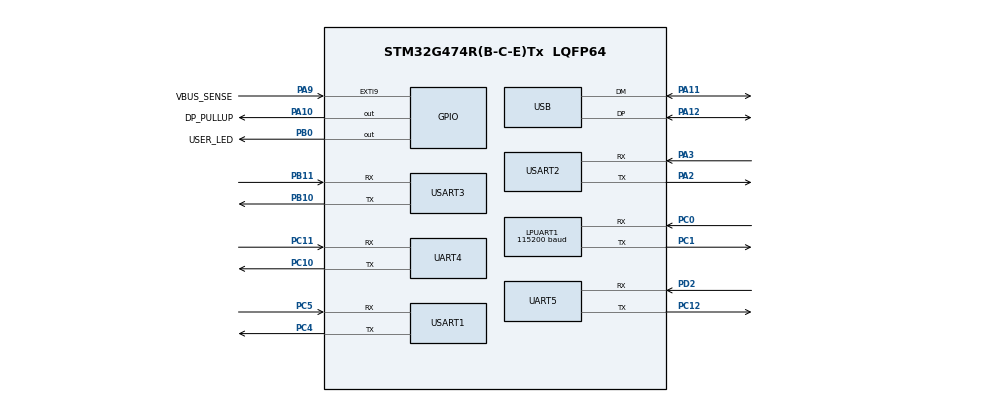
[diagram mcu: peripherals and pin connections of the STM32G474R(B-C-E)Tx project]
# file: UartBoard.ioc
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Dma.LPUART1_RX.0.Direction=DMA_PERIPH_TO_MEMORY
Dma.LPUART1_RX.0.EventEnable=DISABLE
Dma.LPUART1_RX.0.Instance=DMA1_Channel1
Dma.LPUART1_RX.0.MemDataAlignment=DMA_MDATAALIGN_BYTE
Dma.LPUART1_RX.0.MemInc=DMA_MINC_ENABLE
Dma.LPUART1_RX.0.Mode=DMA_NORMAL
Dma.LPUART1_RX.0.PeriphDataAlignment=DMA_PDATAALIGN_BYTE
Dma.LPUART1_RX.0.PeriphInc=DMA_PINC_DISABLE
Dma.LPUART1_RX.0.Polarity=HAL_DMAMUX_REQ_GEN_RISING
Dma.LPUART1_RX.0.Priority=DMA_PRIORITY_LOW
Dma.LPUART1_RX.0.RequestNumber=1
Dma.LPUART1_RX.0.SignalID=NONE
Dma.LPUART1_RX.0.SyncEnable=DISABLE
Dma.LPUART1_RX.0.SyncPolarity=HAL_DMAMUX_SYNC_NO_EVENT
Dma.LPUART1_RX.0.SyncRequestNumber=1
Dma.LPUART1_RX.0.SyncSignalID=NONE
Dma.LPUART1_TX.1.Direction=DMA_MEMORY_TO_PERIPH
Dma.LPUART1_TX.1.EventEnable=DISABLE
Dma.LPUART1_TX.1.Instance=DMA1_Channel2
Dma.LPUART1_TX.1.MemDataAlignment=DMA_MDATAALIGN_BYTE
Dma.LPUART1_TX.1.MemInc=DMA_MINC_ENABLE
Dma.LPUART1_TX.1.Mode=DMA_NORMAL
Dma.LPUART1_TX.1.PeriphDataAlignment=DMA_PDATAALIGN_BYTE
Dma.LPUART1_TX.1.PeriphInc=DMA_PINC_DISABLE
Dma.LPUART1_TX.1.Polarity=HAL_DMAMUX_REQ_GEN_RISING
Dma.LPUART1_TX.1.Priority=DMA_PRIORITY_LOW
Dma.LPUART1_TX.1.RequestNumber=1
Dma.LPUART1_TX.1.SignalID=NONE
Dma.LPUART1_TX.1.SyncEnable=DISABLE
Dma.LPUART1_TX.1.SyncPolarity=HAL_DMAMUX_SYNC_NO_EVENT
Dma.LPUART1_TX.1.SyncRequestNumber=1
Dma.LPUART1_TX.1.SyncSignalID=NONE
Dma.Request0=LPUART1_RX
Dma.Request1=LPUART1_TX
Dma.Request10=UART5_RX
Dma.Request11=UART5_TX
Dma.Request2=USART1_RX
Dma.Request3=USART1_TX
Dma.Request4=USART2_RX
Dma.Request5=USART2_TX
Dma.Request6=USART3_RX
Dma.Request7=USART3_TX
Dma.Request8=UART4_RX
Dma.Request9=UART4_TX
Dma.UART4_RX.8.Direction=DMA_PERIPH_TO_MEMORY
Dma.UART4_RX.8.EventEnable=DISABLE
Dma.UART4_RX.8.Instance=DMA2_Channel1
Dma.UART4_RX.8.MemDataAlignment=DMA_MDATAALIGN_BYTE
Dma.UART4_RX.8.MemInc=DMA_MINC_ENABLE
Dma.UART4_RX.8.Mode=DMA_NORMAL
Dma.UART4_RX.8.PeriphDataAlignment=DMA_PDATAALIGN_BYTE
Dma.UART4_RX.8.PeriphInc=DMA_PINC_DISABLE
Dma.UART4_RX.8.Polarity=HAL_DMAMUX_REQ_GEN_RISING
Dma.UART4_RX.8.Priority=DMA_PRIORITY_LOW
Dma.UART4_RX.8.RequestNumber=1
Dma.UART4_RX.8.SignalID=NONE
Dma.UART4_RX.8.SyncEnable=DISABLE
Dma.UART4_RX.8.SyncPolarity=HAL_DMAMUX_SYNC_NO_EVENT
Dma.UART4_RX.8.SyncRequestNumber=1
Dma.UART4_RX.8.SyncSignalID=NONE
Dma.UART4_TX.9.Direction=DMA_MEMORY_TO_PERIPH
Dma.UART4_TX.9.EventEnable=DISABLE
Dma.UART4_TX.9.Instance=DMA2_Channel2
Dma.UART4_TX.9.MemDataAlignment=DMA_MDATAALIGN_BYTE
Dma.UART4_TX.9.MemInc=DMA_MINC_ENABLE
Dma.UART4_TX.9.Mode=DMA_NORMAL
Dma.UART4_TX.9.PeriphDataAlignment=DMA_PDATAALIGN_BYTE
Dma.UART4_TX.9.PeriphInc=DMA_PINC_DISABLE
Dma.UART4_TX.9.Polarity=HAL_DMAMUX_REQ_GEN_RISING
Dma.UART4_TX.9.Priority=DMA_PRIORITY_LOW
Dma.UART4_TX.9.RequestNumber=1
Dma.UART4_TX.9.SignalID=NONE
Dma.UART4_TX.9.SyncEnable=DISABLE
Dma.UART4_TX.9.SyncPolarity=HAL_DMAMUX_SYNC_NO_EVENT
Dma.UART4_TX.9.SyncRequestNumber=1
Dma.UART4_TX.9.SyncSignalID=NONE
Dma.UART5_RX.10.Direction=DMA_PERIPH_TO_MEMORY
Dma.UART5_RX.10.EventEnable=DISABLE
Dma.UART5_RX.10.Instance=DMA2_Channel3
Dma.UART5_RX.10.MemDataAlignment=DMA_MDATAALIGN_BYTE
Dma.UART5_RX.10.MemInc=DMA_MINC_ENABLE
Dma.UART5_RX.10.Mode=DMA_NORMAL
Dma.UART5_RX.10.PeriphDataAlignment=DMA_PDATAALIGN_BYTE
Dma.UART5_RX.10.PeriphInc=DMA_PINC_DISABLE
Dma.UART5_RX.10.Polarity=HAL_DMAMUX_REQ_GEN_RISING
Dma.UART5_RX.10.Priority=DMA_PRIORITY_LOW
Dma.UART5_RX.10.RequestNumber=1
Dma.UART5_RX.10.SignalID=NONE
Dma.UART5_RX.10.SyncEnable=DISABLE
Dma.UART5_RX.10.SyncPolarity=HAL_DMAMUX_SYNC_NO_EVENT
Dma.UART5_RX.10.SyncRequestNumber=1
Dma.UART5_RX.10.SyncSignalID=NONE
Dma.UART5_TX.11.Direction=DMA_MEMORY_TO_PERIPH
Dma.UART5_TX.11.EventEnable=DISABLE
Dma.UART5_TX.11.Instance=DMA2_Channel4
Dma.UART5_TX.11.MemDataAlignment=DMA_MDATAALIGN_BYTE
Dma.UART5_TX.11.MemInc=DMA_MINC_ENABLE
Dma.UART5_TX.11.Mode=DMA_NORMAL
Dma.UART5_TX.11.PeriphDataAlignment=DMA_PDATAALIGN_BYTE
Dma.UART5_TX.11.PeriphInc=DMA_PINC_DISABLE
Dma.UART5_TX.11.Polarity=HAL_DMAMUX_REQ_GEN_RISING
Dma.UART5_TX.11.Priority=DMA_PRIORITY_LOW
Dma.UART5_TX.11.RequestNumber=1
Dma.UART5_TX.11.SignalID=NONE
Dma.UART5_TX.11.SyncEnable=DISABLE
Dma.UART5_TX.11.SyncPolarity=HAL_DMAMUX_SYNC_NO_EVENT
Dma.UART5_TX.11.SyncRequestNumber=1
Dma.UART5_TX.11.SyncSignalID=NONE
Dma.USART1_RX.2.Direction=DMA_PERIPH_TO_MEMORY
Dma.USART1_RX.2.EventEnable=DISABLE
Dma.USART1_RX.2.Instance=DMA1_Channel3
Dma.USART1_RX.2.MemDataAlignment=DMA_MDATAALIGN_BYTE
Dma.USART1_RX.2.MemInc=DMA_MINC_ENABLE
Dma.USART1_RX.2.Mode=DMA_NORMAL
Dma.USART1_RX.2.PeriphDataAlignment=DMA_PDATAALIGN_BYTE
Dma.USART1_RX.2.PeriphInc=DMA_PINC_DISABLE
Dma.USART1_RX.2.Polarity=HAL_DMAMUX_REQ_GEN_RISING
Dma.USART1_RX.2.Priority=DMA_PRIORITY_LOW
Dma.USART1_RX.2.RequestNumber=1
Dma.USART1_RX.2.SignalID=NONE
Dma.USART1_RX.2.SyncEnable=DISABLE
Dma.USART1_RX.2.SyncPolarity=HAL_DMAMUX_SYNC_NO_EVENT
Dma.USART1_RX.2.SyncRequestNumber=1
Dma.USART1_RX.2.SyncSignalID=NONE
Dma.USART1_TX.3.Direction=DMA_MEMORY_TO_PERIPH
Dma.USART1_TX.3.EventEnable=DISABLE
Dma.USART1_TX.3.Instance=DMA1_Channel4
Dma.USART1_TX.3.MemDataAlignment=DMA_MDATAALIGN_BYTE
Dma.USART1_TX.3.MemInc=DMA_MINC_ENABLE
Dma.USART1_TX.3.Mode=DMA_NORMAL
Dma.USART1_TX.3.PeriphDataAlignment=DMA_PDATAALIGN_BYTE
Dma.USART1_TX.3.PeriphInc=DMA_PINC_DISABLE
Dma.USART1_TX.3.Polarity=HAL_DMAMUX_REQ_GEN_RISING
Dma.USART1_TX.3.Priority=DMA_PRIORITY_LOW
Dma.USART1_TX.3.RequestNumber=1
Dma.USART1_TX.3.SignalID=NONE
Dma.USART1_TX.3.SyncEnable=DISABLE
Dma.USART1_TX.3.SyncPolarity=HAL_DMAMUX_SYNC_NO_EVENT
Dma.USART1_TX.3.SyncRequestNumber=1
Dma.USART1_TX.3.SyncSignalID=NONE
Dma.USART2_RX.4.Direction=DMA_PERIPH_TO_MEMORY
Dma.USART2_RX.4.EventEnable=DISABLE
Dma.USART2_RX.4.Instance=DMA1_Channel5
Dma.USART2_RX.4.MemDataAlignment=DMA_MDATAALIGN_BYTE
Dma.USART2_RX.4.MemInc=DMA_MINC_ENABLE
Dma.USART2_RX.4.Mode=DMA_NORMAL
Dma.USART2_RX.4.PeriphDataAlignment=DMA_PDATAALIGN_BYTE
Dma.USART2_RX.4.PeriphInc=DMA_PINC_DISABLE
Dma.USART2_RX.4.Polarity=HAL_DMAMUX_REQ_GEN_RISING
Dma.USART2_RX.4.Priority=DMA_PRIORITY_LOW
Dma.USART2_RX.4.RequestNumber=1
Dma.USART2_RX.4.SignalID=NONE
Dma.USART2_RX.4.SyncEnable=DISABLE
Dma.USART2_RX.4.SyncPolarity=HAL_DMAMUX_SYNC_NO_EVENT
Dma.USART2_RX.4.SyncRequestNumber=1
Dma.USART2_RX.4.SyncSignalID=NONE
Dma.USART2_TX.5.Direction=DMA_MEMORY_TO_PERIPH
Dma.USART2_TX.5.EventEnable=DISABLE
Dma.USART2_TX.5.Instance=DMA1_Channel6
Dma.USART2_TX.5.MemDataAlignment=DMA_MDATAALIGN_BYTE
Dma.USART2_TX.5.MemInc=DMA_MINC_ENABLE
Dma.USART2_TX.5.Mode=DMA_NORMAL
Dma.USART2_TX.5.PeriphDataAlignment=DMA_PDATAALIGN_BYTE
Dma.USART2_TX.5.PeriphInc=DMA_PINC_DISABLE
Dma.USART2_TX.5.Polarity=HAL_DMAMUX_REQ_GEN_RISING
Dma.USART2_TX.5.Priority=DMA_PRIORITY_LOW
Dma.USART2_TX.5.RequestNumber=1
Dma.USART2_TX.5.SignalID=NONE
Dma.USART2_TX.5.SyncEnable=DISABLE
Dma.USART2_TX.5.SyncPolarity=HAL_DMAMUX_SYNC_NO_EVENT
Dma.USART2_TX.5.SyncRequestNumber=1
Dma.USART2_TX.5.SyncSignalID=NONE
Dma.USART3_RX.6.Direction=DMA_PERIPH_TO_MEMORY
Dma.USART3_RX.6.EventEnable=DISABLE
Dma.USART3_RX.6.Instance=DMA1_Channel7
Dma.USART3_RX.6.MemDataAlignment=DMA_MDATAALIGN_BYTE
Dma.USART3_RX.6.MemInc=DMA_MINC_ENABLE
Dma.USART3_RX.6.Mode=DMA_NORMAL
Dma.USART3_RX.6.PeriphDataAlignment=DMA_PDATAALIGN_BYTE
Dma.USART3_RX.6.PeriphInc=DMA_PINC_DISABLE
Dma.USART3_RX.6.Polarity=HAL_DMAMUX_REQ_GEN_RISING
Dma.USART3_RX.6.Priority=DMA_PRIORITY_LOW
Dma.USART3_RX.6.RequestNumber=1
Dma.USART3_RX.6.SignalID=NONE
Dma.USART3_RX.6.SyncEnable=DISABLE
Dma.USART3_RX.6.SyncPolarity=HAL_DMAMUX_SYNC_NO_EVENT
Dma.USART3_RX.6.SyncRequestNumber=1
Dma.USART3_RX.6.SyncSignalID=NONE
Dma.USART3_TX.7.Direction=DMA_MEMORY_TO_PERIPH
Dma.USART3_TX.7.EventEnable=DISABLE
Dma.USART3_TX.7.Instance=DMA1_Channel8
Dma.USART3_TX.7.MemDataAlignment=DMA_MDATAALIGN_BYTE
Dma.USART3_TX.7.MemInc=DMA_MINC_ENABLE
Dma.USART3_TX.7.Mode=DMA_NORMAL
Dma.USART3_TX.7.PeriphDataAlignment=DMA_PDATAALIGN_BYTE
Dma.USART3_TX.7.PeriphInc=DMA_PINC_DISABLE
Dma.USART3_TX.7.Polarity=HAL_DMAMUX_REQ_GEN_RISING
Dma.USART3_TX.7.Priority=DMA_PRIORITY_LOW
Dma.USART3_TX.7.RequestNumber=1
Dma.USART3_TX.7.SignalID=NONE
Dma.USART3_TX.7.SyncEnable=DISABLE
Dma.USART3_TX.7.SyncPolarity=HAL_DMAMUX_SYNC_NO_EVENT
Dma.USART3_TX.7.SyncRequestNumber=1
Dma.USART3_TX.7.SyncSignalID=NONE
LPUART1.BaudRate=115200
Mcu.Family=STM32G4
Mcu.Name=STM32G474R(B-C-E)Tx
Mcu.Package=LQFP64
NVIC.DMA1_Channel1_IRQn=true\:0\:0\:false\:false\:true\:false\:true\:true
NVIC.DMA1_Channel2_IRQn=true\:0\:0\:false\:false\:true\:false\:true\:true
NVIC.DMA1_Channel3_IRQn=true\:0\:0\:false\:false\:true\:false\:true\:true
NVIC.DMA1_Channel4_IRQn=true\:0\:0\:false\:false\:true\:false\:true\:true
NVIC.DMA1_Channel5_IRQn=true\:0\:0\:false\:false\:true\:false\:true\:true
NVIC.DMA1_Channel6_IRQn=true\:0\:0\:false\:false\:true\:false\:true\:true
NVIC.DMA1_Channel7_IRQn=true\:0\:0\:false\:false\:true\:false\:true\:true
NVIC.DMA1_Channel8_IRQn=true\:0\:0\:false\:false\:true\:false\:true\:true
NVIC.DMA2_Channel1_IRQn=true\:0\:0\:false\:false\:true\:false\:true\:true
NVIC.DMA2_Channel2_IRQn=true\:0\:0\:false\:false\:true\:false\:true\:true
NVIC.DMA2_Channel3_IRQn=true\:0\:0\:false\:false\:true\:false\:true\:true
NVIC.DMA2_Channel4_IRQn=true\:0\:0\:false\:false\:true\:false\:true\:true
NVIC.LPUART1_IRQn=true\:0\:0\:false\:false\:true\:true\:true\:true
NVIC.PriorityGroup=NVIC_PRIORITYGROUP_4
NVIC.UART4_IRQn=true\:0\:0\:false\:false\:true\:true\:true\:true
NVIC.UART5_IRQn=true\:0\:0\:false\:false\:true\:true\:true\:true
NVIC.USART1_IRQn=true\:0\:0\:false\:false\:true\:true\:true\:true
NVIC.USART3_IRQn=true\:0\:0\:false\:false\:true\:true\:true\:true
NVIC.USB_HP_IRQn=true\:0\:0\:false\:false\:true\:true\:true\:true
NVIC.USB_LP_IRQn=true\:0\:0\:false\:false\:true\:true\:true\:true
PA10.GPIO_Label=DP_PULLUP
PA10.Signal=GPIO_Output
PA11.Mode=Device
PA11.Signal=USB_DM
PA12.Mode=Device
PA12.Signal=USB_DP
PA13.Mode=Trace_Asynchronous_SW
PA13.Signal=SYS_JTMS-SWDIO
PA14.Mode=Trace_Asynchronous_SW
PA14.Signal=SYS_JTCK-SWCLK
PA2.Mode=Asynchronous
PA2.Signal=USART2_TX
PA3.Mode=Asynchronous
PA3.Signal=USART2_RX
PA9.GPIO_Label=VBUS_SENSE
PA9.Signal=GPXTI9
PB0.GPIO_Label=USER_LED
PB0.Signal=GPIO_Output
PB10.Mode=Asynchronous
PB10.Signal=USART3_TX
PB11.Mode=Asynchronous
PB11.Signal=USART3_RX
PB3.Mode=Trace_Asynchronous_SW
PB3.Signal=SYS_JTDO-SWO
PC0.Mode=Asynchronous
PC0.Signal=LPUART1_RX
PC1.Mode=Asynchronous
PC1.Signal=LPUART1_TX
PC10.Mode=Asynchronous
PC10.Signal=UART4_TX
PC11.Mode=Asynchronous
PC11.Signal=UART4_RX
PC12.Mode=Asynchronous
PC12.Signal=UART5_TX
PC4.Mode=Asynchronous
PC4.Signal=USART1_TX
PC5.Mode=Asynchronous
PC5.Signal=USART1_RX
PD2.Mode=Asynchronous
PD2.Signal=UART5_RX
PF0-OSC_IN.Mode=HSE-External-Oscillator
PF0-OSC_IN.Signal=RCC_OSC_IN
PF1-OSC_OUT.Mode=HSE-External-Oscillator
PF1-OSC_OUT.Signal=RCC_OSC_OUT
ProjectManager.HeapSize=0x200
ProjectManager.StackSize=0x400
ProjectManager.TargetToolchain=CMake
RCC.ADC12Freq_Value=96000000
RCC.ADC345Freq_Value=96000000
RCC.AHBFreq_Value=96000000
RCC.APB1Freq_Value=96000000
RCC.APB1TimFreq_Value=96000000
RCC.APB2Freq_Value=96000000
RCC.APB2TimFreq_Value=96000000
RCC.CortexFreq_Value=96000000
RCC.EXTERNAL_CLOCK_VALUE=12288000
RCC.HCLKFreq_Value=96000000
RCC.HSE_VALUE=16000000
RCC.HSI48_VALUE=48000000
RCC.HSI_VALUE=16000000
RCC.LSE_VALUE=32768
RCC.PLLN=12
RCC.PLLQ=RCC_PLLQ_DIV4
RCC.PLLSourceVirtual=RCC_PLLSOURCE_HSE
RCC.SYSCLKFreq_VALUE=96000000
RCC.SYSCLKSource=RCC_SYSCLKSOURCE_PLLCLK
RCC.USBFreq_Value=48000000
RCC.VCOOutputFreq_Value=192000000
USART1.VirtualMode-Asynchronous=VM_ASYNC
USART2.VirtualMode-Asynchronous=VM_ASYNC
USART3.VirtualMode-Asynchronous=VM_ASYNC
VP_SYS_VS_DBSignals.Mode=DisableDeadBatterySignals
board=custom

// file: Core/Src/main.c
/* USER CODE BEGIN Header */
/**
  ******************************************************************************
  * @file           : main.c
  * @brief          : Main program body
  ******************************************************************************
  * @attention
  *
  * Copyright (c) 2026 STMicroelectronics.
  * All rights reserved.
  *
  * This software is licensed under terms that can be found in the LICENSE file
  * in the root directory of this software component.
  * If no LICENSE file comes with this software, it is provided AS-IS.
  *
  ******************************************************************************
  */
/* USER CODE END Header */
#include "main.h"

/* USER CODE BEGIN Includes */
// #include "device/dcd.h"
#include "tusb.h"
#include "serialization.h"
#include "deserialization.h"
#include <string.h>
#include <stdio.h>
/* USER CODE END Includes */

UART_HandleTypeDef hlpuart1;
UART_HandleTypeDef huart4;
UART_HandleTypeDef huart5;
UART_HandleTypeDef huart1;
UART_HandleTypeDef huart2;
UART_HandleTypeDef huart3;

PCD_HandleTypeDef hpcd_USB_FS;

/* USER CODE BEGIN PV */
uint8_t lpuart1_out_buf[64];
uint8_t uart1_out_buf[64];
uint8_t uart2_out_buf[64];
uint8_t uart3_out_buf[64];
uint8_t uart4_out_buf[64];
uint8_t uart5_out_buf[64];
/* USER CODE END PV */

void SystemClock_Config(void);
static void MX_GPIO_Init(void);
static void MX_LPUART1_UART_Init(void);
static void MX_UART4_Init(void);
static void MX_UART5_Init(void);
static void MX_USART1_UART_Init(void);
static void MX_USART2_UART_Init(void);
static void MX_USART3_UART_Init(void);
static void MX_USB_PCD_Init(void);

/* USER CODE BEGIN 0 */
static void cdc_task(void);
/* USER CODE END 0 */

int main(void)
{

  /* MCU Configuration--------------------------------------------------------*/

  /* Reset of all peripherals, Initializes the Flash interface and the Systick. */
  HAL_Init();

  /* Configure the system clock */
  SystemClock_Config();

  /* Initialize all configured peripherals */
  MX_GPIO_Init();
  MX_LPUART1_UART_Init();
  MX_UART4_Init();
  MX_UART5_Init();
  MX_USART1_UART_Init();
  MX_USART2_UART_Init();
  MX_USART3_UART_Init();
  MX_USB_PCD_Init();
  /* USER CODE BEGIN 2 */
 // init device stack on configured roothub port
  tusb_rhport_init_t dev_init = {
    .role = TUSB_ROLE_DEVICE,
    .speed = TUSB_SPEED_AUTO
  };
  tusb_init(BOARD_TUD_RHPORT, &dev_init);
  /* USER CODE END 2 */

  /* Infinite loop */
  /* USER CODE BEGIN WHILE */
  while (1)
  {
    tud_task(); // tinyusb device task
    cdc_task();
    /* USER CODE END WHILE */

  }
}

void SystemClock_Config(void)
{
  RCC_OscInitTypeDef RCC_OscInitStruct = {0};
  RCC_ClkInitTypeDef RCC_ClkInitStruct = {0};

  /** Configure the main internal regulator output voltage
  */
  HAL_PWREx_ControlVoltageScaling(PWR_REGULATOR_VOLTAGE_SCALE1);

  /** Initializes the RCC Oscillators according to the specified parameters
  * in the RCC_OscInitTypeDef structure.
  */
  RCC_OscInitStruct.OscillatorType = RCC_OSCILLATORTYPE_HSE;
  RCC_OscInitStruct.HSEState = RCC_HSE_ON;
  RCC_OscInitStruct.PLL.PLLState = RCC_PLL_ON;
  RCC_OscInitStruct.PLL.PLLSource = RCC_PLLSOURCE_HSE;
  RCC_OscInitStruct.PLL.PLLM = RCC_PLLM_DIV2;
  RCC_OscInitStruct.PLL.PLLN = 8;
  RCC_OscInitStruct.PLL.PLLP = RCC_PLLP_DIV2;
  RCC_OscInitStruct.PLL.PLLQ = RCC_PLLQ_DIV2;
  RCC_OscInitStruct.PLL.PLLR = RCC_PLLR_DIV2;
  if (HAL_RCC_OscConfig(&RCC_OscInitStruct) != HAL_OK)
  {
    Error_Handler();
  }

  /** Initializes the CPU, AHB and APB buses clocks
  */
  RCC_ClkInitStruct.ClockType = RCC_CLOCKTYPE_HCLK|RCC_CLOCKTYPE_SYSCLK
                              |RCC_CLOCKTYPE_PCLK1|RCC_CLOCKTYPE_PCLK2;
  RCC_ClkInitStruct.SYSCLKSource = RCC_SYSCLKSOURCE_PLLCLK;
  RCC_ClkInitStruct.AHBCLKDivider = RCC_SYSCLK_DIV2;
  RCC_ClkInitStruct.APB1CLKDivider = RCC_HCLK_DIV1;
  RCC_ClkInitStruct.APB2CLKDivider = RCC_HCLK_DIV1;

  if (HAL_RCC_ClockConfig(&RCC_ClkInitStruct, FLASH_LATENCY_0) != HAL_OK)
  {
    Error_Handler();
  }
}

static void MX_LPUART1_UART_Init(void)
{

  hlpuart1.Instance = LPUART1;
  hlpuart1.Init.BaudRate = 209700;
  hlpuart1.Init.WordLength = UART_WORDLENGTH_8B;
  hlpuart1.Init.StopBits = UART_STOPBITS_1;
  hlpuart1.Init.Parity = UART_PARITY_NONE;
  hlpuart1.Init.Mode = UART_MODE_TX_RX;
  hlpuart1.Init.HwFlowCtl = UART_HWCONTROL_NONE;
  hlpuart1.Init.OneBitSampling = UART_ONE_BIT_SAMPLE_DISABLE;
  hlpuart1.Init.ClockPrescaler = UART_PRESCALER_DIV1;
  hlpuart1.AdvancedInit.AdvFeatureInit = UART_ADVFEATURE_NO_INIT;
  if (HAL_UART_Init(&hlpuart1) != HAL_OK)
  {
    Error_Handler();
  }
  if (HAL_UARTEx_SetTxFifoThreshold(&hlpuart1, UART_TXFIFO_THRESHOLD_1_8) != HAL_OK)
  {
    Error_Handler();
  }
  if (HAL_UARTEx_SetRxFifoThreshold(&hlpuart1, UART_RXFIFO_THRESHOLD_1_8) != HAL_OK)
  {
    Error_Handler();
  }
  if (HAL_UARTEx_DisableFifoMode(&hlpuart1) != HAL_OK)
  {
    Error_Handler();
  }

}

static void MX_UART4_Init(void)
{

  huart4.Instance = UART4;
  huart4.Init.BaudRate = 115200;
  huart4.Init.WordLength = UART_WORDLENGTH_8B;
  huart4.Init.StopBits = UART_STOPBITS_1;
  huart4.Init.Parity = UART_PARITY_NONE;
  huart4.Init.Mode = UART_MODE_TX_RX;
  huart4.Init.HwFlowCtl = UART_HWCONTROL_NONE;
  huart4.Init.OverSampling = UART_OVERSAMPLING_16;
  huart4.Init.OneBitSampling = UART_ONE_BIT_SAMPLE_DISABLE;
  huart4.Init.ClockPrescaler = UART_PRESCALER_DIV1;
  huart4.AdvancedInit.AdvFeatureInit = UART_ADVFEATURE_NO_INIT;
  if (HAL_UART_Init(&huart4) != HAL_OK)
  {
    Error_Handler();
  }
  if (HAL_UARTEx_SetTxFifoThreshold(&huart4, UART_TXFIFO_THRESHOLD_1_8) != HAL_OK)
  {
    Error_Handler();
  }
  if (HAL_UARTEx_SetRxFifoThreshold(&huart4, UART_RXFIFO_THRESHOLD_1_8) != HAL_OK)
  {
    Error_Handler();
  }
  if (HAL_UARTEx_DisableFifoMode(&huart4) != HAL_OK)
  {
    Error_Handler();
  }

}

static void MX_UART5_Init(void)
{

  huart5.Instance = UART5;
  huart5.Init.BaudRate = 115200;
  huart5.Init.WordLength = UART_WORDLENGTH_8B;
  huart5.Init.StopBits = UART_STOPBITS_1;
  huart5.Init.Parity = UART_PARITY_NONE;
  huart5.Init.Mode = UART_MODE_TX_RX;
  huart5.Init.HwFlowCtl = UART_HWCONTROL_RTS_CTS;
  huart5.Init.OverSampling = UART_OVERSAMPLING_16;
  huart5.Init.OneBitSampling = UART_ONE_BIT_SAMPLE_DISABLE;
  huart5.Init.ClockPrescaler = UART_PRESCALER_DIV1;
  huart5.AdvancedInit.AdvFeatureInit = UART_ADVFEATURE_NO_INIT;
  if (HAL_UART_Init(&huart5) != HAL_OK)
  {
    Error_Handler();
  }
  if (HAL_UARTEx_SetTxFifoThreshold(&huart5, UART_TXFIFO_THRESHOLD_1_8) != HAL_OK)
  {
    Error_Handler();
  }
  if (HAL_UARTEx_SetRxFifoThreshold(&huart5, UART_RXFIFO_THRESHOLD_1_8) != HAL_OK)
  {
    Error_Handler();
  }
  if (HAL_UARTEx_DisableFifoMode(&huart5) != HAL_OK)
  {
    Error_Handler();
  }

}

static void MX_USART1_UART_Init(void)
{

  huart1.Instance = USART1;
  huart1.Init.BaudRate = 115200;
  huart1.Init.WordLength = UART_WORDLENGTH_8B;
  huart1.Init.StopBits = UART_STOPBITS_1;
  huart1.Init.Parity = UART_PARITY_NONE;
  huart1.Init.Mode = UART_MODE_TX_RX;
  huart1.Init.HwFlowCtl = UART_HWCONTROL_NONE;
  huart1.Init.OverSampling = UART_OVERSAMPLING_16;
  huart1.Init.OneBitSampling = UART_ONE_BIT_SAMPLE_DISABLE;
  huart1.Init.ClockPrescaler = UART_PRESCALER_DIV1;
  huart1.AdvancedInit.AdvFeatureInit = UART_ADVFEATURE_NO_INIT;
  if (HAL_UART_Init(&huart1) != HAL_OK)
  {
    Error_Handler();
  }
  if (HAL_UARTEx_SetTxFifoThreshold(&huart1, UART_TXFIFO_THRESHOLD_1_8) != HAL_OK)
  {
    Error_Handler();
  }
  if (HAL_UARTEx_SetRxFifoThreshold(&huart1, UART_RXFIFO_THRESHOLD_1_8) != HAL_OK)
  {
    Error_Handler();
  }
  if (HAL_UARTEx_DisableFifoMode(&huart1) != HAL_OK)
  {
    Error_Handler();
  }

}

static void MX_USART2_UART_Init(void)
{

  huart2.Instance = USART2;
  huart2.Init.BaudRate = 115200;
  huart2.Init.WordLength = UART_WORDLENGTH_8B;
  huart2.Init.StopBits = UART_STOPBITS_1;
  huart2.Init.Parity = UART_PARITY_NONE;
  huart2.Init.Mode = UART_MODE_TX_RX;
  huart2.Init.HwFlowCtl = UART_HWCONTROL_NONE;
  huart2.Init.OverSampling = UART_OVERSAMPLING_16;
  huart2.Init.OneBitSampling = UART_ONE_BIT_SAMPLE_DISABLE;
  huart2.Init.ClockPrescaler = UART_PRESCALER_DIV1;
  huart2.AdvancedInit.AdvFeatureInit = UART_ADVFEATURE_NO_INIT;
  if (HAL_RS485Ex_Init(&huart2, UART_DE_POLARITY_HIGH, 0, 0) != HAL_OK)
  {
    Error_Handler();
  }
  if (HAL_UARTEx_SetTxFifoThreshold(&huart2, UART_TXFIFO_THRESHOLD_1_8) != HAL_OK)
  {
    Error_Handler();
  }
  if (HAL_UARTEx_SetRxFifoThreshold(&huart2, UART_RXFIFO_THRESHOLD_1_8) != HAL_OK)
  {
    Error_Handler();
  }
  if (HAL_UARTEx_DisableFifoMode(&huart2) != HAL_OK)
  {
    Error_Handler();
  }

}

static void MX_USART3_UART_Init(void)
{

  huart3.Instance = USART3;
  huart3.Init.BaudRate = 115200;
  huart3.Init.WordLength = UART_WORDLENGTH_8B;
  huart3.Init.StopBits = UART_STOPBITS_1;
  huart3.Init.Parity = UART_PARITY_NONE;
  huart3.Init.Mode = UART_MODE_TX_RX;
  huart3.Init.HwFlowCtl = UART_HWCONTROL_NONE;
  huart3.Init.OverSampling = UART_OVERSAMPLING_16;
  huart3.Init.OneBitSampling = UART_ONE_BIT_SAMPLE_DISABLE;
  huart3.Init.ClockPrescaler = UART_PRESCALER_DIV1;
  huart3.AdvancedInit.AdvFeatureInit = UART_ADVFEATURE_NO_INIT;
  if (HAL_UART_Init(&huart3) != HAL_OK)
  {
    Error_Handler();
  }
  if (HAL_UARTEx_SetTxFifoThreshold(&huart3, UART_TXFIFO_THRESHOLD_1_8) != HAL_OK)
  {
    Error_Handler();
  }
  if (HAL_UARTEx_SetRxFifoThreshold(&huart3, UART_RXFIFO_THRESHOLD_1_8) != HAL_OK)
  {
    Error_Handler();
  }
  if (HAL_UARTEx_DisableFifoMode(&huart3) != HAL_OK)
  {
    Error_Handler();
  }

}

static void MX_USB_PCD_Init(void)
{

  hpcd_USB_FS.Instance = USB;
  hpcd_USB_FS.Init.dev_endpoints = 8;
  hpcd_USB_FS.Init.speed = PCD_SPEED_FULL;
  hpcd_USB_FS.Init.phy_itface = PCD_PHY_EMBEDDED;
  hpcd_USB_FS.Init.Sof_enable = DISABLE;
  hpcd_USB_FS.Init.low_power_enable = DISABLE;
  hpcd_USB_FS.Init.lpm_enable = DISABLE;
  hpcd_USB_FS.Init.battery_charging_enable = DISABLE;
  if (HAL_PCD_Init(&hpcd_USB_FS) != HAL_OK)
  {
    Error_Handler();
  }

}

static void MX_GPIO_Init(void)
{
  GPIO_InitTypeDef GPIO_InitStruct = {0};

  /* GPIO Ports Clock Enable */
  __HAL_RCC_GPIOF_CLK_ENABLE();
  __HAL_RCC_GPIOC_CLK_ENABLE();
  __HAL_RCC_GPIOA_CLK_ENABLE();
  __HAL_RCC_GPIOB_CLK_ENABLE();
  __HAL_RCC_GPIOD_CLK_ENABLE();

  /*Configure GPIO pin Output Level */
  HAL_GPIO_WritePin(USER_LED_GPIO_Port, USER_LED_Pin, GPIO_PIN_RESET);

  /*Configure GPIO pin Output Level */
  HAL_GPIO_WritePin(DP_PULLUP_GPIO_Port, DP_PULLUP_Pin, GPIO_PIN_RESET);

  /*Configure GPIO pin : USER_LED_Pin */
  GPIO_InitStruct.Pin = USER_LED_Pin;
  GPIO_InitStruct.Mode = GPIO_MODE_OUTPUT_PP;
  GPIO_InitStruct.Pull = GPIO_NOPULL;
  GPIO_InitStruct.Speed = GPIO_SPEED_FREQ_LOW;
  HAL_GPIO_Init(USER_LED_GPIO_Port, &GPIO_InitStruct);

  /*Configure GPIO pin : VBUS_SENSE_Pin */
  GPIO_InitStruct.Pin = VBUS_SENSE_Pin;
  GPIO_InitStruct.Mode = GPIO_MODE_IT_RISING;
  GPIO_InitStruct.Pull = GPIO_NOPULL;
  HAL_GPIO_Init(VBUS_SENSE_GPIO_Port, &GPIO_InitStruct);

  /*Configure GPIO pin : DP_PULLUP_Pin */
  GPIO_InitStruct.Pin = DP_PULLUP_Pin;
  GPIO_InitStruct.Mode = GPIO_MODE_OUTPUT_PP;
  GPIO_InitStruct.Pull = GPIO_NOPULL;
  GPIO_InitStruct.Speed = GPIO_SPEED_FREQ_LOW;
  HAL_GPIO_Init(DP_PULLUP_GPIO_Port, &GPIO_InitStruct);

}

/* USER CODE BEGIN 4 */

// Invoked when cdc when line state changed e.g connected/disconnected
// Use to reset to DFU when disconnect with 1200 bps
void tud_cdc_line_state_cb(uint8_t instance, bool dtr, bool rts) {
  (void)rts;

  // DTR = false is counted as disconnected
  if (!dtr) {
    // touch1200 only with first CDC instance (Serial)
    if (instance == 0) {
      cdc_line_coding_t coding;
      tud_cdc_get_line_coding(&coding);
      // if (coding.bit_rate == 1200) {
      //   board_reset_to_bootloader();
      // }
    }
  }
}
static UART_HandleTypeDef *get_huart(const char *topic) {
  if (strcmp(topic, LPUART1_TOPIC) == 0) {
    return &hlpuart1;
  } else if (strcmp(topic, UART1_TOPIC) == 0) {
    return &huart1;
  } else if (strcmp(topic, UART2_TOPIC) == 0) {
    return &huart2;
  }else if (strcmp(topic, UART3_TOPIC) == 0) {
    return &huart3;
  }else if (strcmp(topic, UART4_TOPIC) == 0) {
    return &huart4;
  }else if (strcmp(topic, UART5_TOPIC) == 0) {
    return &huart5;
  }

  return NULL;
}

static void cdc_task(void) {
  // We assume itf 0

  if (tud_cdc_n_available(0)) {
    char json[128];
    uint32_t count = tud_cdc_n_read(0,json, 128);
    char topic[32] = {0};
    uint8_t msg[64] = {0};
    deserialize(topic, 32, msg, 64, json);
    UART_HandleTypeDef *huart = get_huart(topic);

    if (huart == NULL) {
      // Malformed or missing topic??
      return;
    }

    // Can be converted to interrupt based transmission;
    HAL_UART_Transmit(huart, msg, 64, 500);
  }
}
/* USER CODE END 4 */

void Error_Handler(void)
{
  __disable_irq();
  while (1)
  {
  }
}
